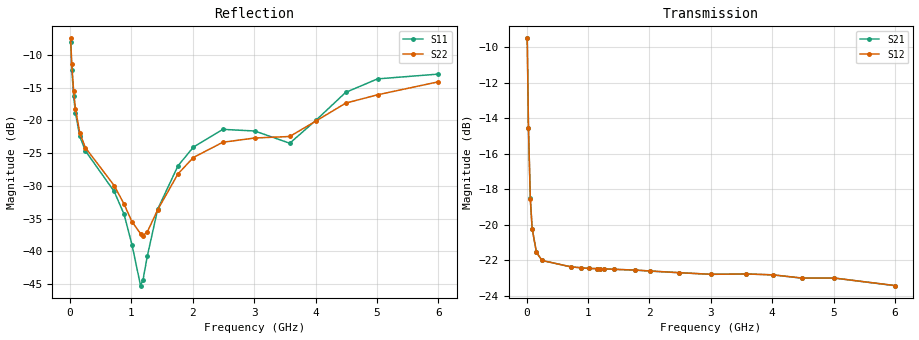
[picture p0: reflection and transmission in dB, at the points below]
! Integrated Device Technology
! Corporate Headquarters
! 6024 Silver Creek Valley Road
! San Jose, CA 95138  USA
! Phone:  1-408-284-8200
! Toll Free:  1-800-223-1366
! Webpage:  http://www.idt.com/
! Timing and RF Division
! 515 Groton Road, Suite 102
! Westford, MA 01886-6024
! Device:  F1951
! Description: 6-bit 0.5 dB Digital Step Attenuator
! Frequency:  100.0 -  4000.00 MHz
! Package:  4x4 mm Thin QFN Plastic Package: 24 pin
! Ports:  2 RF, 6 DC
!  Pin  1  = NC
!  Pin  2  = RF1  =  Port 1
!  Pin  3  = GND
!  Pin  4  = NC
!  Pin  5  = Serial Data Out (SDO)
!  Pin  6  = NC
!  Pin  7  = Reset Bar ( RSTb)
!  Pin  8  = Clock (CLK)
!  Pin  9  = Chip Select Bar (CSb)
!  Pin 10  = NC
!  Pin 11  = Serial Data In (SDI)
!  Pin 12  = NC
!  Pin 13  = NC
!  Pin 14  = VDD
!  Pin 15  = NC
!  Pin 16  = GND
!  Pin 17  = RF2  =  Port 2
!  Pin 18  = NC
!  Pin 19  = GND
!  Pin 20  = GND
!  Pin 21  = GND
!  Pin 22  = GND
!  Pin 23  = GND
!  Pin 24  = GND
! State:  43
! Atten State:  21.5 dB
! Voltage:  +3.30 Volts
! Current:  0.488 mA
! Data:  The device was measured on a F195X evaluation board which has
!  individual transmission lines to the RF pins.  Data was collected
!  de-embedded using a Automatic Fixture Removal [AFR] (Keysight Technologies).
!  The reference plane is the edge of the package pin.
! Misc:  Lot Code  1225BCA
!  Action Tracker AT0399
! Date Measured:  2018-09-13
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# GHz S dB R 50
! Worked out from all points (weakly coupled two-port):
!   600 points, 10 MHz to 6 GHz, reference 50 ohm
!   highest |S21| = -9.50 dB at 10 MHz (marker M1); lowest = -23.4 dB at 6 GHz (marker M2)
!   lowest |S11| = -45.3 dB at 1.15 GHz (marker M3), VSWR 1.01, Z = 49.5 + j0.0288 ohm
!   |S11| at or under -10 dB: 18.28 MHz to end of sweep
!   |S22| runs from -37.6 to -7.5 dB; largest |S21 - S12| = 0.0002
!   S11 on the Smith chart (normalised r, x): 10 MHz: 1.68, -0.90; 30 MHz: 1.16, -0.52; 90 MHz: 0.97, -0.22; 1.76 GHz: 0.96, +0.08; 6 GHz: 0.80, +0.37
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0.01  -7.96 -34.4  -9.50 -31.1  -9.50 -31.1  -7.48 -31.5
0.03  -12.26 -59.5  -14.56 -43.9  -14.56 -44.0  -11.43 -59.6
0.06  -16.24 -79.1  -18.51 -39.8  -18.52 -39.7  -15.58 -80.8
0.09  -18.91 -90.9  -20.21 -32.6  -20.21 -32.6  -18.29 -93.2
0.16  -22.43 -107.7  -21.54 -22.6  -21.54 -22.6  -21.91 -110.2
0.25  -24.64 -118.4  -22.00 -17.3  -22.00 -17.3  -24.16 -121.8
0.72  -30.86 -124.1  -22.36 -15.6  -22.36 -15.7  -29.96 -136.0
0.88  -34.32 -124.6  -22.41 -17.2  -22.41 -17.2  -32.77 -140.5
1.01  -38.99 -131.2  -22.45 -18.5  -22.45 -18.5  -35.49 -149.3
1.15  -45.26 176.9  -22.46 -19.9  -22.46 -19.9  -37.31 -172.5
1.19  -44.36 149.9  -22.47 -20.4  -22.47 -20.4  -37.60 177.7
1.26  -40.74 123.3  -22.47 -21.2  -22.47 -21.2  -37.05 163.8
1.43  -33.55 110.4  -22.50 -23.4  -22.50 -23.4  -33.64 140.2
1.76  -26.95 114.9  -22.54 -27.7  -22.54 -27.7  -28.18 130.6
2.01  -24.10 122.8  -22.60 -31.1  -22.59 -31.1  -25.68 133.5
2.49  -21.38 137.5  -22.69 -37.5  -22.69 -37.6  -23.35 141.3
3.01  -21.63 148.5  -22.78 -44.3  -22.78 -44.3  -22.70 145.0
3.58  -23.50 127.1  -22.76 -51.7  -22.76 -51.7  -22.47 127.4
4.01  -19.97 101.6  -22.81 -57.3  -22.81 -57.3  -20.09 115.1
4.49  -15.74 99.6  -23.00 -63.2  -22.99 -63.2  -17.38 113.6
5.01  -13.67 108.4  -22.99 -67.9  -22.99 -67.9  -16.10 116.4
6  -12.94 106.6  -23.42 -83.5  -23.41 -83.5  -14.12 105.7
